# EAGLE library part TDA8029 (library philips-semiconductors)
Low power single card reader Source: TDA8029.pdf

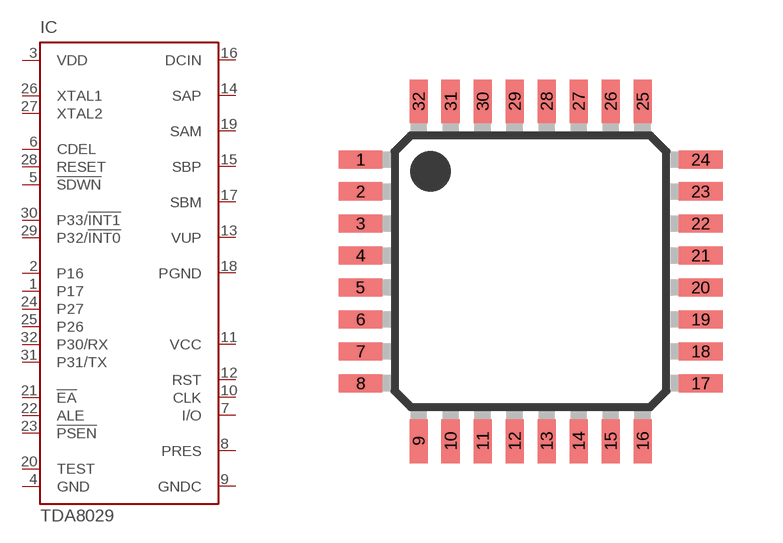
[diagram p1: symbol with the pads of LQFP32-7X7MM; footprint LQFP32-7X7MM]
Designator prefix IC

## TDA8029 (MPN: TDA8029HL/C207,118; OC_FARNELL: unknown; OC_NEWARK: 70R9255)  [LQFP32-7X7MM]
1  P17
2  P16
3  VDD  pwr
4  GND  pwr
5  !SDWN  in
6  CDEL  pas
7  I/O
8  PRES  in
9  GNDC  pas
10  CLK  out
11  VCC  pas
12  RST  out
13  VUP  pas
14  SAP  pas
15  SBP  pas
16  DCIN  pas
17  SBM  pas
18  PGND  pas
19  SAM  pas
20  TEST  pas
21  !EA  in
22  ALE  out
23  !PSEN  out
24  P27
25  P26
26  XTAL1  in
27  XTAL2  out
28  RESET  in
29  P32/!INT0  out
30  P33/!INT1
31  P31/TX
32  P30/RX

## Footprint LQFP32-7X7MM (pad centres in mm)
LQFP32 plastic low profile quad flat package, 32 leads, body 7 x 7 x 1.4 mm Source: TDA8029.pdf
smd 1.1 x 0.45: 1 -4.25,2.8; 2 -4.25,2; 3 -4.25,1.2; 4 -4.25,0.4; 5 -4.25,-0.4; 6 -4.25,-1.2; 7 -4.25,-2; 8 -4.25,-2.8; 17 4.25,-2.8; 18 4.25,-2; 19 4.25,-1.2; 20 4.25,-0.4; 21 4.25,0.4; 22 4.25,1.2; 23 4.25,2; 24 4.25,2.8
smd 0.45 x 1.1: 9 -2.8,-4.25; 10 -2,-4.25; 11 -1.2,-4.25; 12 -0.4,-4.25; 13 0.4,-4.25; 14 1.2,-4.25; 15 2,-4.25; 16 2.8,-4.25; 25 2.8,4.25; 26 2,4.25; 27 1.2,4.25; 28 0.4,4.25; 29 -0.4,4.25; 30 -1.2,4.25; 31 -2,4.25; 32 -2.8,4.25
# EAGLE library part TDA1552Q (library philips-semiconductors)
2 x 22 W BTL stereo car radio power amplifier Source: Data sheet

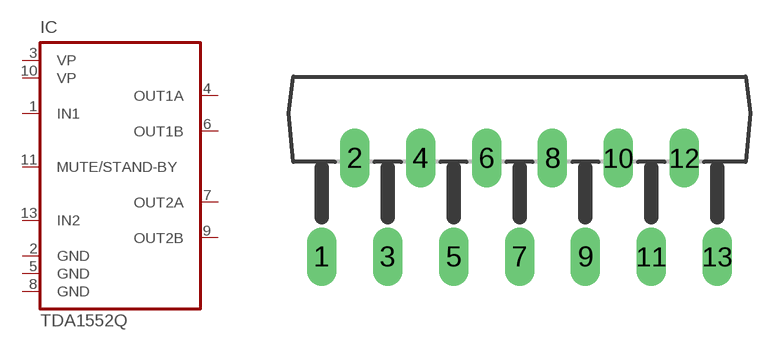
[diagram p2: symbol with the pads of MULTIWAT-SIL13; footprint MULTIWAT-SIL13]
Designator prefix IC

## TDA1552Q  [MULTIWAT-SIL13]
1  IN1  in
2  GND  pwr
3  VP  in
4  OUT1A  out
5  GND  pwr
6  OUT1B  out
7  OUT2A  out
8  GND  pwr
9  OUT2B  out
10  VP  in
11  MUTE/STAND-BY  in
13  IN2  in

## Footprint MULTIWAT-SIL13 (pad centres in mm)
DBS13P plastic DIL-bent-SIL power package 13 leads (lead length 12 mm) SOT141-6 Source: TDA1516BQ_1.pdf
drill 1 pad 1.5 long: 1 -10.2,-5.08; 2 -8.5,0; 3 -6.8,-5.08; 4 -5.1,0; 5 -3.4,-5.08; 6 -1.7,0; 7 0,-5.08; 8 1.7,0; 9 3.4,-5.08; 10 5.1,0; 11 6.8,-5.08; 12 8.5,0; 13 10.2,-5.08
